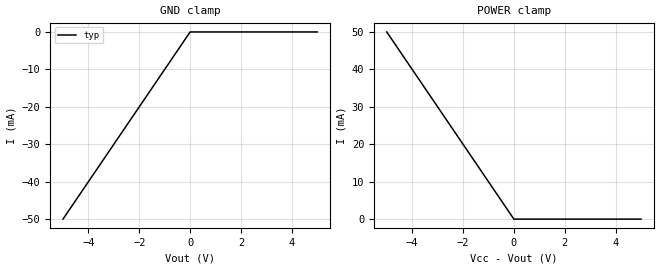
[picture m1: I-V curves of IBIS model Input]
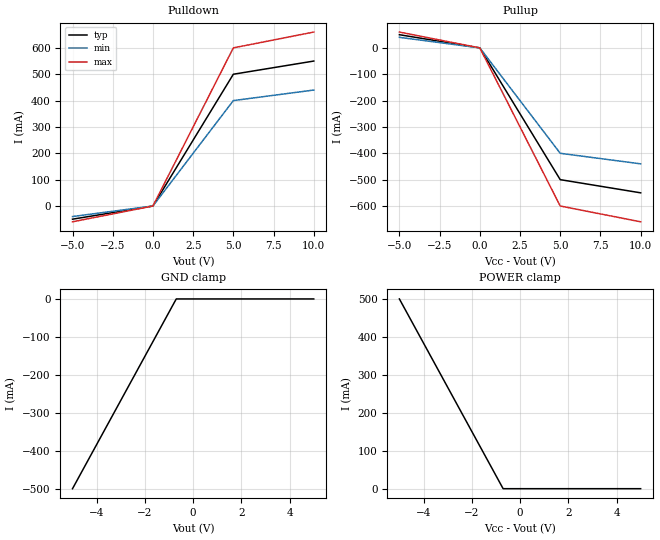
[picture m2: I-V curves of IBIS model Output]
[IBIS Ver]   1.1  |Let's test a comment
[Comment char]  #_char
[File name]   ibis_v1_1.ibs
[File Rev]   1.0  #Let's test a comment
[Date]   26/08/2021
[Source]   This is the
   source for the files
[Notes]   We can have some
   Notes
[Disclaimer] This is NOT a valid component.
[Component]   Virtual
[Manufacturer]  KiCad
[Package]
R_pkg   50m   40m   60m
L_pkg   2n   NA   NA
C_pkg   10p   NA   NA
[Pin]   signal_name   model_name   R_pin   L_pin   C_pin
  1   VCC   POWER   5mm   2n   NA
  2   GND   GND   55m   NA   NA
  3   X   Input   55m   NA   0.2p
  4   Y   Output   55m   2n   0.2p
# Models and submodels in the file (2): Input (Input), Output (Output)
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[Model]   Input
Model_type   Input
Polarity   Non-Inverting
Enable   Active-High
Vinl = 0.8V
Vinh = 2.0V
C_comp   1.0pF   0.5pF   2.0pF
[Voltage range]   5.0V   4.5V   5.5V
[GND_clamp]
#  Voltage   I(typ)   I(min)   I(max)
-5V       -50mA      NA         NA
0V        0A         NA         NA
5V        0A         NA         NA
[POWER_clamp]
#  Voltage   I(typ)   I(min)   I(max)
-5V       50mA       NA         NA
0V        0A         NA         NA
5V        0A         NA         NA
[Model]   Output
Model_type   Output
Polarity   Non-Inverting
Enable   Active-High
C_comp   10.0pF   8.0pF   15.0pF
[Voltage range]   5.0V   4.5V   5.5V
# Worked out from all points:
#   slope of the pulldown table from 0 to 0.75 V, typ, clamps not added: 10 ohm
#   slope of the pullup table from 0 to 0.75 V, typ, clamps not added: 10 ohm
[Pulldown]
#  Voltage   I(typ)   I(min)   I(max)
-5V       -50mA      -40mA      -60mA
0V        0A         0A         0A
5V        500mA      400mA      600mA
10V       550mA      440mA      660mA
[Pullup]
#  Voltage   I(typ)   I(min)   I(max)
-5V       50mA       40mA       60mA
0V        0A         0A         0A
5V        -500mA     -400mA     -600mA
10V       -550mA     -440mA     -660mA
[GND_clamp]
#  Voltage   I(typ)   I(min)   I(max)
-5V       -500mA     NA         NA
-700mV    0A         NA         NA
5V        0A         NA         NA
[POWER_clamp]
#  Voltage   I(typ)   I(min)   I(max)
-5V       500mA      NA         NA
-700mV    0A         NA         NA
5V        0A         NA         NA
[Ramp]
# variable   typ   min   max
dV/dt_r   3.0/30n   2.8/30n   NA
dV/dt_f   3.0/20n   2.8/20n   3.2/20n
